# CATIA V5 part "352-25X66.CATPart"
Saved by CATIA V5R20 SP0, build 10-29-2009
Part number: 352-25X66
Definition: NONE
Nomenclature: 352-25X66
Source: Unknown
Description: 352-25X66
Bounding box of the stored display mesh (mm): x 0 to 66, y -17 to 17, z -17 to 17
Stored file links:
  C:\Users\Utente\Desktop\IO LAVORO\3D X SITO CF\X SITO\PLASTICA\352\352-25X66.CATPart

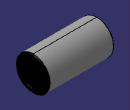
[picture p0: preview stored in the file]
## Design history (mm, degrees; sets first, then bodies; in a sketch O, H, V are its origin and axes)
Body1 "352-25X66" (main body)
  Solid1: solid without history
